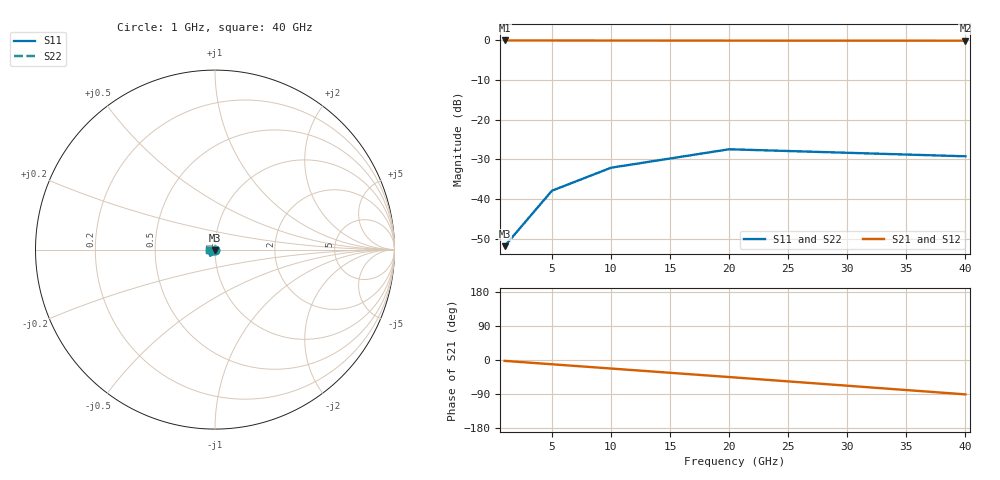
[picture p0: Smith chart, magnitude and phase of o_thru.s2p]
! Generated by circuitRF - EM: openEMS
! circuitRF-EM setup: g_thru_sheets
! circuitRF-EM layout: thru/layout/thru.clay
! circuitRF-EM written: 2026-11-04 17:26:00Z
! circuitRF-EM geometry: 7a18eea52115d3c4
! circuitRF-EM mesh: 004bf1be6bea5130
! circuitRF-EM ports: e0915e1a10e1aaad
! circuitRF-EM model: openEMS 0.37.0 (v0.37.0, CSXCAD v0.7.0)
! Port[1] = port/1
! Port[2] = port/2
! circuitRF-EM port 1: 'port/1' from 'airbox/zmin' to 'Metal1/1', wave (fed line, voltage and current probes at the reference plane), 50 Ohm
! circuitRF-EM port 2: 'port/2' from 'airbox/zmin' to 'Metal1/1', wave (fed line, voltage and current probes at the reference plane), 50 Ohm
! circuitRF-EM 3D grid: 255 x 44 x 14 = 157080 cells; smallest cell 6.827 um on y, set by 'Metal1/1' edge at y = -20 um (thirds rule, inside; local cell 24 um); 'Metal1/1' edge at y = 20 um (thirds rule, inside; local cell 24 um)
! circuitRF-EM 3D openEMS run port 1: dt 2.08287E-14 s (estimate 2.08366E-14 s), 15900 steps, port signals 53.8 dB and energy 41.3 dB against 50 dB, stopped by circuitRF on the ports' decay, converged
! circuitRF-EM 3D openEMS run port 2: dt 2.08287E-14 s (estimate 2.08366E-14 s), 15900 steps, port signals 54.5 dB and energy 41.3 dB against 50 dB, stopped by circuitRF on the ports' decay, converged
! circuitRF-EM 3D dielectric loss fitted at: 20.5 GHz
! circuitRF-EM 3D perfect conductors: none
! circuitRF-EM 3D operating temperature: 20 C
! circuitRF-EM 3D DC row: circuitRF conduction solve of the conductors, 368 elements, 0.06 s; ports as terminal pairs
! circuitRF-EM: re-running the EM setup rewrites this file. If circuitRF reports it as stale, the layout's cross-section changed after this file was written.
# GHz S RI R 50
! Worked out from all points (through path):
!   5 points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, 1 GHz to 40 GHz, reference 50 ohm
!   highest |S21| = -0.01 dB at 1 GHz (marker M1); lowest = -0.1 dB at 40 GHz (marker M2)
!   lowest |S11| = -51.9 dB at 1 GHz (marker M3), VSWR 1.01, Z = 50.1 - j0.239 ohm
!   |S11| at or under -10 dB: start of sweep to end of sweep
!   |S22| runs from -51.9 to -27.4 dB; largest |S21 - S12| = 1.8e-06
1  0.000872 -0.00239  0.9978 -0.0394  0.9978 -0.0394  0.000872 -0.00239
5  -0.000785 -0.0127  0.9786 -0.1946  0.9786 -0.1946  -0.000785 -0.0127
10  -0.007 -0.0238  0.9208 -0.381  0.9208 -0.381  -0.007 -0.0238
20  -0.027 -0.0328  0.7033 -0.7026  0.7033 -0.7026  -0.027 -0.0328
40  -0.0343 -0.00415  -0.0128 -0.9915  -0.0128 -0.9915  -0.0343 -0.00416
